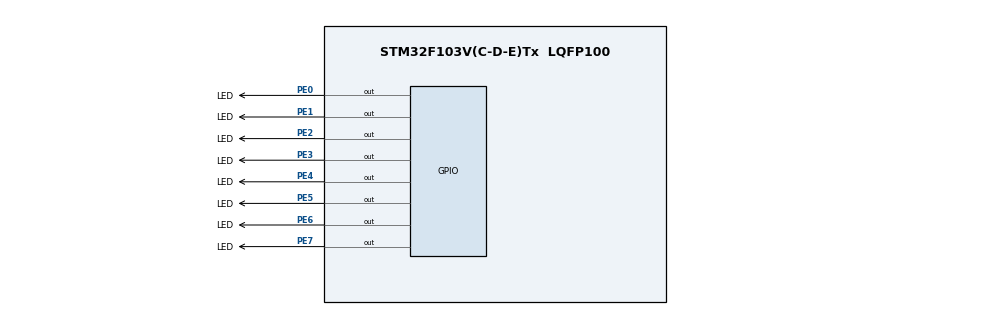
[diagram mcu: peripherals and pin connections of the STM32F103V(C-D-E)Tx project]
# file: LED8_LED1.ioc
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Mcu.Family=STM32F1
Mcu.Name=STM32F103V(C-D-E)Tx
Mcu.Package=LQFP100
NVIC.PriorityGroup=NVIC_PRIORITYGROUP_4
NVIC.TIM2_IRQn=true\:2\:0\:true\:false\:true\:true\:true
OSC_IN.Mode=HSE-External-Oscillator
OSC_IN.Signal=RCC_OSC_IN
OSC_OUT.Mode=HSE-External-Oscillator
OSC_OUT.Signal=RCC_OSC_OUT
PA13.Mode=Serial_Wire
PA13.Signal=SYS_JTMS-SWDIO
PA14.Mode=Serial_Wire
PA14.Signal=SYS_JTCK-SWCLK
PC14-OSC32_IN.Mode=LSE-External-Oscillator
PC14-OSC32_IN.Signal=RCC_OSC32_IN
PC15-OSC32_OUT.Mode=LSE-External-Oscillator
PC15-OSC32_OUT.Signal=RCC_OSC32_OUT
PE0.GPIO_Label=LED
PE0.GPIO_ModeDefaultOutputPP=GPIO_MODE_OUTPUT_PP
PE0.GPIO_PuPd=GPIO_NOPULL
PE0.GPIO_Speed=GPIO_SPEED_FREQ_HIGH
PE0.PinState=GPIO_PIN_SET
PE0.Signal=GPIO_Output
PE1.GPIO_Label=LED
PE1.GPIO_ModeDefaultOutputPP=GPIO_MODE_OUTPUT_PP
PE1.GPIO_PuPd=GPIO_NOPULL
PE1.GPIO_Speed=GPIO_SPEED_FREQ_HIGH
PE1.PinState=GPIO_PIN_SET
PE1.Signal=GPIO_Output
PE2.GPIO_Label=LED
PE2.GPIO_ModeDefaultOutputPP=GPIO_MODE_OUTPUT_PP
PE2.GPIO_PuPd=GPIO_NOPULL
PE2.GPIO_Speed=GPIO_SPEED_FREQ_HIGH
PE2.PinState=GPIO_PIN_SET
PE2.Signal=GPIO_Output
PE3.GPIO_Label=LED
PE3.GPIO_ModeDefaultOutputPP=GPIO_MODE_OUTPUT_PP
PE3.GPIO_PuPd=GPIO_NOPULL
PE3.GPIO_Speed=GPIO_SPEED_FREQ_HIGH
PE3.PinState=GPIO_PIN_SET
PE3.Signal=GPIO_Output
PE4.GPIO_Label=LED
PE4.GPIO_ModeDefaultOutputPP=GPIO_MODE_OUTPUT_PP
PE4.GPIO_PuPd=GPIO_NOPULL
PE4.GPIO_Speed=GPIO_SPEED_FREQ_HIGH
PE4.PinState=GPIO_PIN_SET
PE4.Signal=GPIO_Output
PE5.GPIO_Label=LED
PE5.GPIO_ModeDefaultOutputPP=GPIO_MODE_OUTPUT_PP
PE5.GPIO_PuPd=GPIO_NOPULL
PE5.GPIO_Speed=GPIO_SPEED_FREQ_HIGH
PE5.PinState=GPIO_PIN_SET
PE5.Signal=GPIO_Output
PE6.GPIO_Label=LED
PE6.GPIO_ModeDefaultOutputPP=GPIO_MODE_OUTPUT_PP
PE6.GPIO_PuPd=GPIO_NOPULL
PE6.GPIO_Speed=GPIO_SPEED_FREQ_HIGH
PE6.PinState=GPIO_PIN_SET
PE6.Signal=GPIO_Output
PE7.GPIO_Label=LED
PE7.GPIO_ModeDefaultOutputPP=GPIO_MODE_OUTPUT_PP
PE7.GPIO_PuPd=GPIO_NOPULL
PE7.GPIO_Speed=GPIO_SPEED_FREQ_HIGH
PE7.PinState=GPIO_PIN_SET
PE7.Signal=GPIO_Output
ProjectManager.HeapSize=0x200
ProjectManager.StackSize=0x400
ProjectManager.TargetToolchain=MDK-ARM V5
RCC.AHBFreq_Value=72000000
RCC.APB1CLKDivider=RCC_HCLK_DIV4
RCC.APB1Freq_Value=18000000
RCC.APB1TimFreq_Value=36000000
RCC.APB2CLKDivider=RCC_HCLK_DIV2
RCC.APB2Freq_Value=36000000
RCC.APB2TimFreq_Value=72000000
RCC.HCLKFreq_Value=72000000
RCC.PLLMUL=RCC_PLL_MUL9
RCC.PLLSourceVirtual=RCC_PLLSOURCE_HSE
RCC.SYSCLKFreq_VALUE=72000000
RCC.SYSCLKSource=RCC_SYSCLKSOURCE_PLLCLK
RCC.USBFreq_Value=72000000
TIM2.Period=15000-1
TIM2.Prescaler=3600-1
VP_TIM2_VS_ClockSourceINT.Mode=Internal
board=custom

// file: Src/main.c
/* USER CODE BEGIN Header */
/**
  ******************************************************************************
  * @file           : main.c
  * @brief          : Main program body
  ******************************************************************************
  * @attention
  *
  * <h2><center>&copy; Copyright (c) 2022 STMicroelectronics.
  * All rights reserved.</center></h2>
  *
  * This software component is licensed by ST under BSD 3-Clause license,
  * the "License"; You may not use this file except in compliance with the
  * License. You may obtain a copy of the License at:
  *                        opensource.org/licenses/BSD-3-Clause
  *
  ******************************************************************************
  */
/* USER CODE END Header */

#include "main.h"
#include "tim.h"
#include "gpio.h"

/* USER CODE BEGIN PV */
uint16_t num = 1;
/* USER CODE END PV */

void SystemClock_Config(void);

int main(void)
{

  /* MCU Configuration--------------------------------------------------------*/

  /* Reset of all peripherals, Initializes the Flash interface and the Systick. */
  HAL_Init();

  /* Configure the system clock */
  SystemClock_Config();

  /* Initialize all configured peripherals */
  MX_GPIO_Init();
  MX_TIM2_Init();
  /* USER CODE BEGIN 2 */
HAL_TIM_Base_Start_IT(&htim2);
  /* USER CODE END 2 */

  /* Infinite loop */
  while (1)
  {

  }
}

void SystemClock_Config(void)
{
  RCC_OscInitTypeDef RCC_OscInitStruct = {0};
  RCC_ClkInitTypeDef RCC_ClkInitStruct = {0};

  /** Initializes the CPU, AHB and APB busses clocks
  */
  RCC_OscInitStruct.OscillatorType = RCC_OSCILLATORTYPE_HSE;
  RCC_OscInitStruct.HSEState = RCC_HSE_ON;
  RCC_OscInitStruct.HSEPredivValue = RCC_HSE_PREDIV_DIV1;
  RCC_OscInitStruct.HSIState = RCC_HSI_ON;
  RCC_OscInitStruct.PLL.PLLState = RCC_PLL_ON;
  RCC_OscInitStruct.PLL.PLLSource = RCC_PLLSOURCE_HSE;
  RCC_OscInitStruct.PLL.PLLMUL = RCC_PLL_MUL9;
  if (HAL_RCC_OscConfig(&RCC_OscInitStruct) != HAL_OK)
  {
    Error_Handler();
  }
  /** Initializes the CPU, AHB and APB busses clocks
  */
  RCC_ClkInitStruct.ClockType = RCC_CLOCKTYPE_HCLK|RCC_CLOCKTYPE_SYSCLK
                              |RCC_CLOCKTYPE_PCLK1|RCC_CLOCKTYPE_PCLK2;
  RCC_ClkInitStruct.SYSCLKSource = RCC_SYSCLKSOURCE_PLLCLK;
  RCC_ClkInitStruct.AHBCLKDivider = RCC_SYSCLK_DIV1;
  RCC_ClkInitStruct.APB1CLKDivider = RCC_HCLK_DIV4;
  RCC_ClkInitStruct.APB2CLKDivider = RCC_HCLK_DIV1;

  if (HAL_RCC_ClockConfig(&RCC_ClkInitStruct, FLASH_LATENCY_2) != HAL_OK)
  {
    Error_Handler();
  }
}

/* USER CODE BEGIN 4 */
void HAL_TIM_PeriodElapsedCallback(TIM_HandleTypeDef *htim){
	if(TIM2 == htim -> Instance){

		num>0x80?num=1:0;

		HAL_GPIO_WritePin(GPIOE,0xff,1);
		HAL_GPIO_WritePin(GPIOE,num,0);

		num <<=1;
	}
}
/* USER CODE END 4 */

void Error_Handler(void)
{
}

/************************ (C) COPYRIGHT STMicroelectronics *****END OF FILE****/
